# Generated by FakeRAM 2.0
VERSION 5.7 ;
BUSBITCHARS "[]" ;
PROPERTYDEFINITIONS
  MACRO width INTEGER ;
  MACRO depth INTEGER ;
  MACRO banks INTEGER ;
END PROPERTYDEFINITIONS
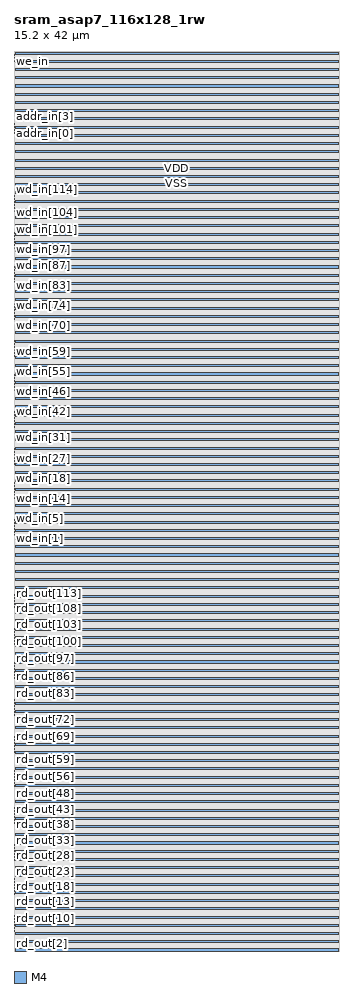
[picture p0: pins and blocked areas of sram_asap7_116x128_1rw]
MACRO sram_asap7_116x128_1rw
  PROPERTY width 116 ;
  PROPERTY depth 128 ;
  PROPERTY banks 1 ;
  FOREIGN sram_asap7_116x128_1rw 0 0 ;
  SYMMETRY X Y R90 ;
  SIZE 15.200 BY 42.000 ;
  CLASS BLOCK ;
  PIN rd_out[0]
    DIRECTION OUTPUT ;
    USE SIGNAL ;
    SHAPE ABUTMENT ;
    PORT
      LAYER M4 ;
      RECT 0.000 0.048 0.024 0.072 ;
    END
  END rd_out[0]
  PIN rd_out[1]
    DIRECTION OUTPUT ;
    USE SIGNAL ;
    SHAPE ABUTMENT ;
    PORT
      LAYER M4 ;
      RECT 0.000 0.192 0.024 0.216 ;
    END
  END rd_out[1]
  PIN rd_out[2]
    DIRECTION OUTPUT ;
    USE SIGNAL ;
    SHAPE ABUTMENT ;
    PORT
      LAYER M4 ;
      RECT 0.000 0.336 0.024 0.360 ;
    END
  END rd_out[2]
  PIN rd_out[3]
    DIRECTION OUTPUT ;
    USE SIGNAL ;
    SHAPE ABUTMENT ;
    PORT
      LAYER M4 ;
      RECT 0.000 0.480 0.024 0.504 ;
    END
  END rd_out[3]
  PIN rd_out[4]
    DIRECTION OUTPUT ;
    USE SIGNAL ;
    SHAPE ABUTMENT ;
    PORT
      LAYER M4 ;
      RECT 0.000 0.624 0.024 0.648 ;
    END
  END rd_out[4]
  PIN rd_out[5]
    DIRECTION OUTPUT ;
    USE SIGNAL ;
    SHAPE ABUTMENT ;
    PORT
      LAYER M4 ;
      RECT 0.000 0.768 0.024 0.792 ;
    END
  END rd_out[5]
  PIN rd_out[6]
    DIRECTION OUTPUT ;
    USE SIGNAL ;
    SHAPE ABUTMENT ;
    PORT
      LAYER M4 ;
      RECT 0.000 0.912 0.024 0.936 ;
    END
  END rd_out[6]
  PIN rd_out[7]
    DIRECTION OUTPUT ;
    USE SIGNAL ;
    SHAPE ABUTMENT ;
    PORT
      LAYER M4 ;
      RECT 0.000 1.056 0.024 1.080 ;
    END
  END rd_out[7]
  PIN rd_out[8]
    DIRECTION OUTPUT ;
    USE SIGNAL ;
    SHAPE ABUTMENT ;
    PORT
      LAYER M4 ;
      RECT 0.000 1.200 0.024 1.224 ;
    END
  END rd_out[8]
  PIN rd_out[9]
    DIRECTION OUTPUT ;
    USE SIGNAL ;
    SHAPE ABUTMENT ;
    PORT
      LAYER M4 ;
      RECT 0.000 1.344 0.024 1.368 ;
    END
  END rd_out[9]
  PIN rd_out[10]
    DIRECTION OUTPUT ;
    USE SIGNAL ;
    SHAPE ABUTMENT ;
    PORT
      LAYER M4 ;
      RECT 0.000 1.488 0.024 1.512 ;
    END
  END rd_out[10]
  PIN rd_out[11]
    DIRECTION OUTPUT ;
    USE SIGNAL ;
    SHAPE ABUTMENT ;
    PORT
      LAYER M4 ;
      RECT 0.000 1.632 0.024 1.656 ;
    END
  END rd_out[11]
  PIN rd_out[12]
    DIRECTION OUTPUT ;
    USE SIGNAL ;
    SHAPE ABUTMENT ;
    PORT
      LAYER M4 ;
      RECT 0.000 1.776 0.024 1.800 ;
    END
  END rd_out[12]
  PIN rd_out[13]
    DIRECTION OUTPUT ;
    USE SIGNAL ;
    SHAPE ABUTMENT ;
    PORT
      LAYER M4 ;
      RECT 0.000 1.920 0.024 1.944 ;
    END
  END rd_out[13]
  PIN rd_out[14]
    DIRECTION OUTPUT ;
    USE SIGNAL ;
    SHAPE ABUTMENT ;
    PORT
      LAYER M4 ;
      RECT 0.000 2.064 0.024 2.088 ;
    END
  END rd_out[14]
  PIN rd_out[15]
    DIRECTION OUTPUT ;
    USE SIGNAL ;
    SHAPE ABUTMENT ;
    PORT
      LAYER M4 ;
      RECT 0.000 2.208 0.024 2.232 ;
    END
  END rd_out[15]
  PIN rd_out[16]
    DIRECTION OUTPUT ;
    USE SIGNAL ;
    SHAPE ABUTMENT ;
    PORT
      LAYER M4 ;
      RECT 0.000 2.352 0.024 2.376 ;
    END
  END rd_out[16]
  PIN rd_out[17]
    DIRECTION OUTPUT ;
    USE SIGNAL ;
    SHAPE ABUTMENT ;
    PORT
      LAYER M4 ;
      RECT 0.000 2.496 0.024 2.520 ;
    END
  END rd_out[17]
  PIN rd_out[18]
    DIRECTION OUTPUT ;
    USE SIGNAL ;
    SHAPE ABUTMENT ;
    PORT
      LAYER M4 ;
      RECT 0.000 2.640 0.024 2.664 ;
    END
  END rd_out[18]
  PIN rd_out[19]
    DIRECTION OUTPUT ;
    USE SIGNAL ;
    SHAPE ABUTMENT ;
    PORT
      LAYER M4 ;
      RECT 0.000 2.784 0.024 2.808 ;
    END
  END rd_out[19]
  PIN rd_out[20]
    DIRECTION OUTPUT ;
    USE SIGNAL ;
    SHAPE ABUTMENT ;
    PORT
      LAYER M4 ;
      RECT 0.000 2.928 0.024 2.952 ;
    END
  END rd_out[20]
  PIN rd_out[21]
    DIRECTION OUTPUT ;
    USE SIGNAL ;
    SHAPE ABUTMENT ;
    PORT
      LAYER M4 ;
      RECT 0.000 3.072 0.024 3.096 ;
    END
  END rd_out[21]
  PIN rd_out[22]
    DIRECTION OUTPUT ;
    USE SIGNAL ;
    SHAPE ABUTMENT ;
    PORT
      LAYER M4 ;
      RECT 0.000 3.216 0.024 3.240 ;
    END
  END rd_out[22]
  PIN rd_out[23]
    DIRECTION OUTPUT ;
    USE SIGNAL ;
    SHAPE ABUTMENT ;
    PORT
      LAYER M4 ;
      RECT 0.000 3.360 0.024 3.384 ;
    END
  END rd_out[23]
  PIN rd_out[24]
    DIRECTION OUTPUT ;
    USE SIGNAL ;
    SHAPE ABUTMENT ;
    PORT
      LAYER M4 ;
      RECT 0.000 3.504 0.024 3.528 ;
    END
  END rd_out[24]
  PIN rd_out[25]
    DIRECTION OUTPUT ;
    USE SIGNAL ;
    SHAPE ABUTMENT ;
    PORT
      LAYER M4 ;
      RECT 0.000 3.648 0.024 3.672 ;
    END
  END rd_out[25]
  PIN rd_out[26]
    DIRECTION OUTPUT ;
    USE SIGNAL ;
    SHAPE ABUTMENT ;
    PORT
      LAYER M4 ;
      RECT 0.000 3.792 0.024 3.816 ;
    END
  END rd_out[26]
  PIN rd_out[27]
    DIRECTION OUTPUT ;
    USE SIGNAL ;
    SHAPE ABUTMENT ;
    PORT
      LAYER M4 ;
      RECT 0.000 3.936 0.024 3.960 ;
    END
  END rd_out[27]
  PIN rd_out[28]
    DIRECTION OUTPUT ;
    USE SIGNAL ;
    SHAPE ABUTMENT ;
    PORT
      LAYER M4 ;
      RECT 0.000 4.080 0.024 4.104 ;
    END
  END rd_out[28]
  PIN rd_out[29]
    DIRECTION OUTPUT ;
    USE SIGNAL ;
    SHAPE ABUTMENT ;
    PORT
      LAYER M4 ;
      RECT 0.000 4.224 0.024 4.248 ;
    END
  END rd_out[29]
  PIN rd_out[30]
    DIRECTION OUTPUT ;
    USE SIGNAL ;
    SHAPE ABUTMENT ;
    PORT
      LAYER M4 ;
      RECT 0.000 4.368 0.024 4.392 ;
    END
  END rd_out[30]
  PIN rd_out[31]
    DIRECTION OUTPUT ;
    USE SIGNAL ;
    SHAPE ABUTMENT ;
    PORT
      LAYER M4 ;
      RECT 0.000 4.512 0.024 4.536 ;
    END
  END rd_out[31]
  PIN rd_out[32]
    DIRECTION OUTPUT ;
    USE SIGNAL ;
    SHAPE ABUTMENT ;
    PORT
      LAYER M4 ;
      RECT 0.000 4.656 0.024 4.680 ;
    END
  END rd_out[32]
  PIN rd_out[33]
    DIRECTION OUTPUT ;
    USE SIGNAL ;
    SHAPE ABUTMENT ;
    PORT
      LAYER M4 ;
      RECT 0.000 4.800 0.024 4.824 ;
    END
  END rd_out[33]
  PIN rd_out[34]
    DIRECTION OUTPUT ;
    USE SIGNAL ;
    SHAPE ABUTMENT ;
    PORT
      LAYER M4 ;
      RECT 0.000 4.944 0.024 4.968 ;
    END
  END rd_out[34]
  PIN rd_out[35]
    DIRECTION OUTPUT ;
    USE SIGNAL ;
    SHAPE ABUTMENT ;
    PORT
      LAYER M4 ;
      RECT 0.000 5.088 0.024 5.112 ;
    END
  END rd_out[35]
  PIN rd_out[36]
    DIRECTION OUTPUT ;
    USE SIGNAL ;
    SHAPE ABUTMENT ;
    PORT
      LAYER M4 ;
      RECT 0.000 5.232 0.024 5.256 ;
    END
  END rd_out[36]
  PIN rd_out[37]
    DIRECTION OUTPUT ;
    USE SIGNAL ;
    SHAPE ABUTMENT ;
    PORT
      LAYER M4 ;
      RECT 0.000 5.376 0.024 5.400 ;
    END
  END rd_out[37]
  PIN rd_out[38]
    DIRECTION OUTPUT ;
    USE SIGNAL ;
    SHAPE ABUTMENT ;
    PORT
      LAYER M4 ;
      RECT 0.000 5.520 0.024 5.544 ;
    END
  END rd_out[38]
  PIN rd_out[39]
    DIRECTION OUTPUT ;
    USE SIGNAL ;
    SHAPE ABUTMENT ;
    PORT
      LAYER M4 ;
      RECT 0.000 5.664 0.024 5.688 ;
    END
  END rd_out[39]
  PIN rd_out[40]
    DIRECTION OUTPUT ;
    USE SIGNAL ;
    SHAPE ABUTMENT ;
    PORT
      LAYER M4 ;
      RECT 0.000 5.808 0.024 5.832 ;
    END
  END rd_out[40]
  PIN rd_out[41]
    DIRECTION OUTPUT ;
    USE SIGNAL ;
    SHAPE ABUTMENT ;
    PORT
      LAYER M4 ;
      RECT 0.000 5.952 0.024 5.976 ;
    END
  END rd_out[41]
  PIN rd_out[42]
    DIRECTION OUTPUT ;
    USE SIGNAL ;
    SHAPE ABUTMENT ;
    PORT
      LAYER M4 ;
      RECT 0.000 6.096 0.024 6.120 ;
    END
  END rd_out[42]
  PIN rd_out[43]
    DIRECTION OUTPUT ;
    USE SIGNAL ;
    SHAPE ABUTMENT ;
    PORT
      LAYER M4 ;
      RECT 0.000 6.240 0.024 6.264 ;
    END
  END rd_out[43]
  PIN rd_out[44]
    DIRECTION OUTPUT ;
    USE SIGNAL ;
    SHAPE ABUTMENT ;
    PORT
      LAYER M4 ;
      RECT 0.000 6.384 0.024 6.408 ;
    END
  END rd_out[44]
  PIN rd_out[45]
    DIRECTION OUTPUT ;
    USE SIGNAL ;
    SHAPE ABUTMENT ;
    PORT
      LAYER M4 ;
      RECT 0.000 6.528 0.024 6.552 ;
    END
  END rd_out[45]
  PIN rd_out[46]
    DIRECTION OUTPUT ;
    USE SIGNAL ;
    SHAPE ABUTMENT ;
    PORT
      LAYER M4 ;
      RECT 0.000 6.672 0.024 6.696 ;
    END
  END rd_out[46]
  PIN rd_out[47]
    DIRECTION OUTPUT ;
    USE SIGNAL ;
    SHAPE ABUTMENT ;
    PORT
      LAYER M4 ;
      RECT 0.000 6.816 0.024 6.840 ;
    END
  END rd_out[47]
  PIN rd_out[48]
    DIRECTION OUTPUT ;
    USE SIGNAL ;
    SHAPE ABUTMENT ;
    PORT
      LAYER M4 ;
      RECT 0.000 6.960 0.024 6.984 ;
    END
  END rd_out[48]
  PIN rd_out[49]
    DIRECTION OUTPUT ;
    USE SIGNAL ;
    SHAPE ABUTMENT ;
    PORT
      LAYER M4 ;
      RECT 0.000 7.104 0.024 7.128 ;
    END
  END rd_out[49]
  PIN rd_out[50]
    DIRECTION OUTPUT ;
    USE SIGNAL ;
    SHAPE ABUTMENT ;
    PORT
      LAYER M4 ;
      RECT 0.000 7.248 0.024 7.272 ;
    END
  END rd_out[50]
  PIN rd_out[51]
    DIRECTION OUTPUT ;
    USE SIGNAL ;
    SHAPE ABUTMENT ;
    PORT
      LAYER M4 ;
      RECT 0.000 7.392 0.024 7.416 ;
    END
  END rd_out[51]
  PIN rd_out[52]
    DIRECTION OUTPUT ;
    USE SIGNAL ;
    SHAPE ABUTMENT ;
    PORT
      LAYER M4 ;
      RECT 0.000 7.536 0.024 7.560 ;
    END
  END rd_out[52]
  PIN rd_out[53]
    DIRECTION OUTPUT ;
    USE SIGNAL ;
    SHAPE ABUTMENT ;
    PORT
      LAYER M4 ;
      RECT 0.000 7.680 0.024 7.704 ;
    END
  END rd_out[53]
  PIN rd_out[54]
    DIRECTION OUTPUT ;
    USE SIGNAL ;
    SHAPE ABUTMENT ;
    PORT
      LAYER M4 ;
      RECT 0.000 7.824 0.024 7.848 ;
    END
  END rd_out[54]
  PIN rd_out[55]
    DIRECTION OUTPUT ;
    USE SIGNAL ;
    SHAPE ABUTMENT ;
    PORT
      LAYER M4 ;
      RECT 0.000 7.968 0.024 7.992 ;
    END
  END rd_out[55]
  PIN rd_out[56]
    DIRECTION OUTPUT ;
    USE SIGNAL ;
    SHAPE ABUTMENT ;
    PORT
      LAYER M4 ;
      RECT 0.000 8.112 0.024 8.136 ;
    END
  END rd_out[56]
  PIN rd_out[57]
    DIRECTION OUTPUT ;
    USE SIGNAL ;
    SHAPE ABUTMENT ;
    PORT
      LAYER M4 ;
      RECT 0.000 8.256 0.024 8.280 ;
    END
  END rd_out[57]
  PIN rd_out[58]
    DIRECTION OUTPUT ;
    USE SIGNAL ;
    SHAPE ABUTMENT ;
    PORT
      LAYER M4 ;
      RECT 0.000 8.400 0.024 8.424 ;
    END
  END rd_out[58]
  PIN rd_out[59]
    DIRECTION OUTPUT ;
    USE SIGNAL ;
    SHAPE ABUTMENT ;
    PORT
      LAYER M4 ;
      RECT 0.000 8.544 0.024 8.568 ;
    END
  END rd_out[59]
  PIN rd_out[60]
    DIRECTION OUTPUT ;
    USE SIGNAL ;
    SHAPE ABUTMENT ;
    PORT
      LAYER M4 ;
      RECT 0.000 8.688 0.024 8.712 ;
    END
  END rd_out[60]
  PIN rd_out[61]
    DIRECTION OUTPUT ;
    USE SIGNAL ;
    SHAPE ABUTMENT ;
    PORT
      LAYER M4 ;
      RECT 0.000 8.832 0.024 8.856 ;
    END
  END rd_out[61]
  PIN rd_out[62]
    DIRECTION OUTPUT ;
    USE SIGNAL ;
    SHAPE ABUTMENT ;
    PORT
      LAYER M4 ;
      RECT 0.000 8.976 0.024 9.000 ;
    END
  END rd_out[62]
  PIN rd_out[63]
    DIRECTION OUTPUT ;
    USE SIGNAL ;
    SHAPE ABUTMENT ;
    PORT
      LAYER M4 ;
      RECT 0.000 9.120 0.024 9.144 ;
    END
  END rd_out[63]
  PIN rd_out[64]
    DIRECTION OUTPUT ;
    USE SIGNAL ;
    SHAPE ABUTMENT ;
    PORT
      LAYER M4 ;
      RECT 0.000 9.264 0.024 9.288 ;
    END
  END rd_out[64]
  PIN rd_out[65]
    DIRECTION OUTPUT ;
    USE SIGNAL ;
    SHAPE ABUTMENT ;
    PORT
      LAYER M4 ;
      RECT 0.000 9.408 0.024 9.432 ;
    END
  END rd_out[65]
  PIN rd_out[66]
    DIRECTION OUTPUT ;
    USE SIGNAL ;
    SHAPE ABUTMENT ;
    PORT
      LAYER M4 ;
      RECT 0.000 9.552 0.024 9.576 ;
    END
  END rd_out[66]
  PIN rd_out[67]
    DIRECTION OUTPUT ;
    USE SIGNAL ;
    SHAPE ABUTMENT ;
    PORT
      LAYER M4 ;
      RECT 0.000 9.696 0.024 9.720 ;
    END
  END rd_out[67]
  PIN rd_out[68]
    DIRECTION OUTPUT ;
    USE SIGNAL ;
    SHAPE ABUTMENT ;
    PORT
      LAYER M4 ;
      RECT 0.000 9.840 0.024 9.864 ;
    END
  END rd_out[68]
  PIN rd_out[69]
    DIRECTION OUTPUT ;
    USE SIGNAL ;
    SHAPE ABUTMENT ;
    PORT
      LAYER M4 ;
      RECT 0.000 9.984 0.024 10.008 ;
    END
  END rd_out[69]
  PIN rd_out[70]
    DIRECTION OUTPUT ;
    USE SIGNAL ;
    SHAPE ABUTMENT ;
    PORT
      LAYER M4 ;
      RECT 0.000 10.128 0.024 10.152 ;
    END
  END rd_out[70]
  PIN rd_out[71]
    DIRECTION OUTPUT ;
    USE SIGNAL ;
    SHAPE ABUTMENT ;
    PORT
      LAYER M4 ;
      RECT 0.000 10.272 0.024 10.296 ;
    END
  END rd_out[71]
  PIN rd_out[72]
    DIRECTION OUTPUT ;
    USE SIGNAL ;
    SHAPE ABUTMENT ;
    PORT
      LAYER M4 ;
      RECT 0.000 10.416 0.024 10.440 ;
    END
  END rd_out[72]
  PIN rd_out[73]
    DIRECTION OUTPUT ;
    USE SIGNAL ;
    SHAPE ABUTMENT ;
    PORT
      LAYER M4 ;
      RECT 0.000 10.560 0.024 10.584 ;
    END
  END rd_out[73]
  PIN rd_out[74]
    DIRECTION OUTPUT ;
    USE SIGNAL ;
    SHAPE ABUTMENT ;
    PORT
      LAYER M4 ;
      RECT 0.000 10.704 0.024 10.728 ;
    END
  END rd_out[74]
  PIN rd_out[75]
    DIRECTION OUTPUT ;
    USE SIGNAL ;
    SHAPE ABUTMENT ;
    PORT
      LAYER M4 ;
      RECT 0.000 10.848 0.024 10.872 ;
    END
  END rd_out[75]
  PIN rd_out[76]
    DIRECTION OUTPUT ;
    USE SIGNAL ;
    SHAPE ABUTMENT ;
    PORT
      LAYER M4 ;
      RECT 0.000 10.992 0.024 11.016 ;
    END
  END rd_out[76]
  PIN rd_out[77]
    DIRECTION OUTPUT ;
    USE SIGNAL ;
    SHAPE ABUTMENT ;
    PORT
      LAYER M4 ;
      RECT 0.000 11.136 0.024 11.160 ;
    END
  END rd_out[77]
  PIN rd_out[78]
    DIRECTION OUTPUT ;
    USE SIGNAL ;
    SHAPE ABUTMENT ;
    PORT
      LAYER M4 ;
      RECT 0.000 11.280 0.024 11.304 ;
    END
  END rd_out[78]
  PIN rd_out[79]
    DIRECTION OUTPUT ;
    USE SIGNAL ;
    SHAPE ABUTMENT ;
    PORT
      LAYER M4 ;
      RECT 0.000 11.424 0.024 11.448 ;
    END
  END rd_out[79]
  PIN rd_out[80]
    DIRECTION OUTPUT ;
    USE SIGNAL ;
    SHAPE ABUTMENT ;
    PORT
      LAYER M4 ;
      RECT 0.000 11.568 0.024 11.592 ;
    END
  END rd_out[80]
  PIN rd_out[81]
    DIRECTION OUTPUT ;
    USE SIGNAL ;
    SHAPE ABUTMENT ;
    PORT
      LAYER M4 ;
      RECT 0.000 11.712 0.024 11.736 ;
    END
  END rd_out[81]
  PIN rd_out[82]
    DIRECTION OUTPUT ;
    USE SIGNAL ;
    SHAPE ABUTMENT ;
    PORT
      LAYER M4 ;
      RECT 0.000 11.856 0.024 11.880 ;
    END
  END rd_out[82]
  PIN rd_out[83]
    DIRECTION OUTPUT ;
    USE SIGNAL ;
    SHAPE ABUTMENT ;
    PORT
      LAYER M4 ;
      RECT 0.000 12.000 0.024 12.024 ;
    END
  END rd_out[83]
  PIN rd_out[84]
    DIRECTION OUTPUT ;
    USE SIGNAL ;
    SHAPE ABUTMENT ;
    PORT
      LAYER M4 ;
      RECT 0.000 12.144 0.024 12.168 ;
    END
  END rd_out[84]
  PIN rd_out[85]
    DIRECTION OUTPUT ;
    USE SIGNAL ;
    SHAPE ABUTMENT ;
    PORT
      LAYER M4 ;
      RECT 0.000 12.288 0.024 12.312 ;
    END
  END rd_out[85]
  PIN rd_out[86]
    DIRECTION OUTPUT ;
    USE SIGNAL ;
    SHAPE ABUTMENT ;
    PORT
      LAYER M4 ;
      RECT 0.000 12.432 0.024 12.456 ;
    END
  END rd_out[86]
  PIN rd_out[87]
    DIRECTION OUTPUT ;
    USE SIGNAL ;
    SHAPE ABUTMENT ;
    PORT
      LAYER M4 ;
      RECT 0.000 12.576 0.024 12.600 ;
    END
  END rd_out[87]
  PIN rd_out[88]
    DIRECTION OUTPUT ;
    USE SIGNAL ;
    SHAPE ABUTMENT ;
    PORT
      LAYER M4 ;
      RECT 0.000 12.720 0.024 12.744 ;
    END
  END rd_out[88]
  PIN rd_out[89]
    DIRECTION OUTPUT ;
    USE SIGNAL ;
    SHAPE ABUTMENT ;
    PORT
      LAYER M4 ;
      RECT 0.000 12.864 0.024 12.888 ;
    END
  END rd_out[89]
  PIN rd_out[90]
    DIRECTION OUTPUT ;
    USE SIGNAL ;
    SHAPE ABUTMENT ;
    PORT
      LAYER M4 ;
      RECT 0.000 13.008 0.024 13.032 ;
    END
  END rd_out[90]
  PIN rd_out[91]
    DIRECTION OUTPUT ;
    USE SIGNAL ;
    SHAPE ABUTMENT ;
    PORT
      LAYER M4 ;
      RECT 0.000 13.152 0.024 13.176 ;
    END
  END rd_out[91]
  PIN rd_out[92]
    DIRECTION OUTPUT ;
    USE SIGNAL ;
    SHAPE ABUTMENT ;
    PORT
      LAYER M4 ;
      RECT 0.000 13.296 0.024 13.320 ;
    END
  END rd_out[92]
  PIN rd_out[93]
    DIRECTION OUTPUT ;
    USE SIGNAL ;
    SHAPE ABUTMENT ;
    PORT
      LAYER M4 ;
      RECT 0.000 13.440 0.024 13.464 ;
    END
  END rd_out[93]
  PIN rd_out[94]
    DIRECTION OUTPUT ;
    USE SIGNAL ;
    SHAPE ABUTMENT ;
    PORT
      LAYER M4 ;
      RECT 0.000 13.584 0.024 13.608 ;
    END
  END rd_out[94]
  PIN rd_out[95]
    DIRECTION OUTPUT ;
    USE SIGNAL ;
    SHAPE ABUTMENT ;
    PORT
      LAYER M4 ;
      RECT 0.000 13.728 0.024 13.752 ;
    END
  END rd_out[95]
  PIN rd_out[96]
    DIRECTION OUTPUT ;
    USE SIGNAL ;
    SHAPE ABUTMENT ;
    PORT
      LAYER M4 ;
      RECT 0.000 13.872 0.024 13.896 ;
    END
  END rd_out[96]
  PIN rd_out[97]
    DIRECTION OUTPUT ;
    USE SIGNAL ;
    SHAPE ABUTMENT ;
    PORT
      LAYER M4 ;
      RECT 0.000 14.016 0.024 14.040 ;
    END
  END rd_out[97]
  PIN rd_out[98]
    DIRECTION OUTPUT ;
    USE SIGNAL ;
    SHAPE ABUTMENT ;
    PORT
      LAYER M4 ;
      RECT 0.000 14.160 0.024 14.184 ;
    END
  END rd_out[98]
  PIN rd_out[99]
    DIRECTION OUTPUT ;
    USE SIGNAL ;
    SHAPE ABUTMENT ;
    PORT
      LAYER M4 ;
      RECT 0.000 14.304 0.024 14.328 ;
    END
  END rd_out[99]
  PIN rd_out[100]
    DIRECTION OUTPUT ;
    USE SIGNAL ;
    SHAPE ABUTMENT ;
    PORT
      LAYER M4 ;
      RECT 0.000 14.448 0.024 14.472 ;
    END
  END rd_out[100]
  PIN rd_out[101]
    DIRECTION OUTPUT ;
    USE SIGNAL ;
    SHAPE ABUTMENT ;
    PORT
      LAYER M4 ;
      RECT 0.000 14.592 0.024 14.616 ;
    END
  END rd_out[101]
  PIN rd_out[102]
    DIRECTION OUTPUT ;
    USE SIGNAL ;
    SHAPE ABUTMENT ;
    PORT
      LAYER M4 ;
      RECT 0.000 14.736 0.024 14.760 ;
    END
  END rd_out[102]
  PIN rd_out[103]
    DIRECTION OUTPUT ;
    USE SIGNAL ;
    SHAPE ABUTMENT ;
    PORT
      LAYER M4 ;
      RECT 0.000 14.880 0.024 14.904 ;
    END
  END rd_out[103]
  PIN rd_out[104]
    DIRECTION OUTPUT ;
    USE SIGNAL ;
    SHAPE ABUTMENT ;
    PORT
      LAYER M4 ;
      RECT 0.000 15.024 0.024 15.048 ;
    END
  END rd_out[104]
  PIN rd_out[105]
    DIRECTION OUTPUT ;
    USE SIGNAL ;
    SHAPE ABUTMENT ;
    PORT
      LAYER M4 ;
      RECT 0.000 15.168 0.024 15.192 ;
    END
  END rd_out[105]
  PIN rd_out[106]
    DIRECTION OUTPUT ;
    USE SIGNAL ;
    SHAPE ABUTMENT ;
    PORT
      LAYER M4 ;
      RECT 0.000 15.312 0.024 15.336 ;
    END
  END rd_out[106]
  PIN rd_out[107]
    DIRECTION OUTPUT ;
    USE SIGNAL ;
    SHAPE ABUTMENT ;
    PORT
      LAYER M4 ;
      RECT 0.000 15.456 0.024 15.480 ;
    END
  END rd_out[107]
  PIN rd_out[108]
    DIRECTION OUTPUT ;
    USE SIGNAL ;
    SHAPE ABUTMENT ;
    PORT
      LAYER M4 ;
      RECT 0.000 15.600 0.024 15.624 ;
    END
  END rd_out[108]
  PIN rd_out[109]
    DIRECTION OUTPUT ;
    USE SIGNAL ;
    SHAPE ABUTMENT ;
    PORT
      LAYER M4 ;
      RECT 0.000 15.744 0.024 15.768 ;
    END
  END rd_out[109]
  PIN rd_out[110]
    DIRECTION OUTPUT ;
    USE SIGNAL ;
    SHAPE ABUTMENT ;
    PORT
      LAYER M4 ;
      RECT 0.000 15.888 0.024 15.912 ;
    END
  END rd_out[110]
  PIN rd_out[111]
    DIRECTION OUTPUT ;
    USE SIGNAL ;
    SHAPE ABUTMENT ;
    PORT
      LAYER M4 ;
      RECT 0.000 16.032 0.024 16.056 ;
    END
  END rd_out[111]
  PIN rd_out[112]
    DIRECTION OUTPUT ;
    USE SIGNAL ;
    SHAPE ABUTMENT ;
    PORT
      LAYER M4 ;
      RECT 0.000 16.176 0.024 16.200 ;
    END
  END rd_out[112]
  PIN rd_out[113]
    DIRECTION OUTPUT ;
    USE SIGNAL ;
    SHAPE ABUTMENT ;
    PORT
      LAYER M4 ;
      RECT 0.000 16.320 0.024 16.344 ;
    END
  END rd_out[113]
  PIN rd_out[114]
    DIRECTION OUTPUT ;
    USE SIGNAL ;
    SHAPE ABUTMENT ;
    PORT
      LAYER M4 ;
      RECT 0.000 16.464 0.024 16.488 ;
    END
  END rd_out[114]
  PIN rd_out[115]
    DIRECTION OUTPUT ;
    USE SIGNAL ;
    SHAPE ABUTMENT ;
    PORT
      LAYER M4 ;
      RECT 0.000 16.608 0.024 16.632 ;
    END
  END rd_out[115]
  PIN wd_in[0]
    DIRECTION INPUT ;
    USE SIGNAL ;
    SHAPE ABUTMENT ;
    PORT
      LAYER M4 ;
      RECT 0.000 19.104 0.024 19.128 ;
    END
  END wd_in[0]
  PIN wd_in[1]
    DIRECTION INPUT ;
    USE SIGNAL ;
    SHAPE ABUTMENT ;
    PORT
      LAYER M4 ;
      RECT 0.000 19.248 0.024 19.272 ;
    END
  END wd_in[1]
  PIN wd_in[2]
    DIRECTION INPUT ;
    USE SIGNAL ;
    SHAPE ABUTMENT ;
    PORT
      LAYER M4 ;
      RECT 0.000 19.392 0.024 19.416 ;
    END
  END wd_in[2]
  PIN wd_in[3]
    DIRECTION INPUT ;
    USE SIGNAL ;
    SHAPE ABUTMENT ;
    PORT
      LAYER M4 ;
      RECT 0.000 19.536 0.024 19.560 ;
    END
  END wd_in[3]
  PIN wd_in[4]
    DIRECTION INPUT ;
    USE SIGNAL ;
    SHAPE ABUTMENT ;
    PORT
      LAYER M4 ;
      RECT 0.000 19.680 0.024 19.704 ;
    END
  END wd_in[4]
  PIN wd_in[5]
    DIRECTION INPUT ;
    USE SIGNAL ;
    SHAPE ABUTMENT ;
    PORT
      LAYER M4 ;
      RECT 0.000 19.824 0.024 19.848 ;
    END
  END wd_in[5]
  PIN wd_in[6]
    DIRECTION INPUT ;
    USE SIGNAL ;
    SHAPE ABUTMENT ;
    PORT
      LAYER M4 ;
      RECT 0.000 19.968 0.024 19.992 ;
    END
  END wd_in[6]
  PIN wd_in[7]
    DIRECTION INPUT ;
    USE SIGNAL ;
    SHAPE ABUTMENT ;
    PORT
      LAYER M4 ;
      RECT 0.000 20.112 0.024 20.136 ;
    END
  END wd_in[7]
  PIN wd_in[8]
    DIRECTION INPUT ;
    USE SIGNAL ;
    SHAPE ABUTMENT ;
    PORT
      LAYER M4 ;
      RECT 0.000 20.256 0.024 20.280 ;
    END
  END wd_in[8]
  PIN wd_in[9]
    DIRECTION INPUT ;
    USE SIGNAL ;
    SHAPE ABUTMENT ;
    PORT
      LAYER M4 ;
      RECT 0.000 20.400 0.024 20.424 ;
    END
  END wd_in[9]
  PIN wd_in[10]
    DIRECTION INPUT ;
    USE SIGNAL ;
    SHAPE ABUTMENT ;
    PORT
      LAYER M4 ;
      RECT 0.000 20.544 0.024 20.568 ;
    END
  END wd_in[10]
  PIN wd_in[11]
    DIRECTION INPUT ;
    USE SIGNAL ;
    SHAPE ABUTMENT ;
    PORT
      LAYER M4 ;
      RECT 0.000 20.688 0.024 20.712 ;
    END
  END wd_in[11]
  PIN wd_in[12]
    DIRECTION INPUT ;
    USE SIGNAL ;
    SHAPE ABUTMENT ;
    PORT
      LAYER M4 ;
      RECT 0.000 20.832 0.024 20.856 ;
    END
  END wd_in[12]
  PIN wd_in[13]
    DIRECTION INPUT ;
    USE SIGNAL ;
    SHAPE ABUTMENT ;
    PORT
      LAYER M4 ;
      RECT 0.000 20.976 0.024 21.000 ;
    END
  END wd_in[13]
  PIN wd_in[14]
    DIRECTION INPUT ;
    USE SIGNAL ;
    SHAPE ABUTMENT ;
    PORT
      LAYER M4 ;
      RECT 0.000 21.120 0.024 21.144 ;
    END
  END wd_in[14]
  PIN wd_in[15]
    DIRECTION INPUT ;
    USE SIGNAL ;
    SHAPE ABUTMENT ;
    PORT
      LAYER M4 ;
      RECT 0.000 21.264 0.024 21.288 ;
    END
  END wd_in[15]
  PIN wd_in[16]
    DIRECTION INPUT ;
    USE SIGNAL ;
    SHAPE ABUTMENT ;
    PORT
      LAYER M4 ;
      RECT 0.000 21.408 0.024 21.432 ;
    END
  END wd_in[16]
  PIN wd_in[17]
    DIRECTION INPUT ;
    USE SIGNAL ;
    SHAPE ABUTMENT ;
    PORT
      LAYER M4 ;
      RECT 0.000 21.552 0.024 21.576 ;
    END
  END wd_in[17]
  PIN wd_in[18]
    DIRECTION INPUT ;
    USE SIGNAL ;
    SHAPE ABUTMENT ;
    PORT
      LAYER M4 ;
      RECT 0.000 21.696 0.024 21.720 ;
    END
  END wd_in[18]
  PIN wd_in[19]
    DIRECTION INPUT ;
    USE SIGNAL ;
    SHAPE ABUTMENT ;
    PORT
      LAYER M4 ;
      RECT 0.000 21.840 0.024 21.864 ;
    END
  END wd_in[19]
  PIN wd_in[20]
    DIRECTION INPUT ;
    USE SIGNAL ;
    SHAPE ABUTMENT ;
    PORT
      LAYER M4 ;
      RECT 0.000 21.984 0.024 22.008 ;
    END
  END wd_in[20]
  PIN wd_in[21]
    DIRECTION INPUT ;
    USE SIGNAL ;
    SHAPE ABUTMENT ;
    PORT
      LAYER M4 ;
      RECT 0.000 22.128 0.024 22.152 ;
    END
  END wd_in[21]
  PIN wd_in[22]
    DIRECTION INPUT ;
    USE SIGNAL ;
    SHAPE ABUTMENT ;
    PORT
      LAYER M4 ;
      RECT 0.000 22.272 0.024 22.296 ;
    END
  END wd_in[22]
  PIN wd_in[23]
    DIRECTION INPUT ;
    USE SIGNAL ;
    SHAPE ABUTMENT ;
    PORT
      LAYER M4 ;
      RECT 0.000 22.416 0.024 22.440 ;
    END
  END wd_in[23]
  PIN wd_in[24]
    DIRECTION INPUT ;
    USE SIGNAL ;
    SHAPE ABUTMENT ;
    PORT
      LAYER M4 ;
      RECT 0.000 22.560 0.024 22.584 ;
    END
  END wd_in[24]
  PIN wd_in[25]
    DIRECTION INPUT ;
    USE SIGNAL ;
    SHAPE ABUTMENT ;
    PORT
      LAYER M4 ;
      RECT 0.000 22.704 0.024 22.728 ;
    END
  END wd_in[25]
  PIN wd_in[26]
    DIRECTION INPUT ;
    USE SIGNAL ;
    SHAPE ABUTMENT ;
    PORT
      LAYER M4 ;
      RECT 0.000 22.848 0.024 22.872 ;
    END
  END wd_in[26]
  PIN wd_in[27]
    DIRECTION INPUT ;
    USE SIGNAL ;
    SHAPE ABUTMENT ;
    PORT
      LAYER M4 ;
      RECT 0.000 22.992 0.024 23.016 ;
    END
  END wd_in[27]
  PIN wd_in[28]
    DIRECTION INPUT ;
    USE SIGNAL ;
    SHAPE ABUTMENT ;
    PORT
      LAYER M4 ;
      RECT 0.000 23.136 0.024 23.160 ;
    END
  END wd_in[28]
  PIN wd_in[29]
    DIRECTION INPUT ;
    USE SIGNAL ;
    SHAPE ABUTMENT ;
    PORT
      LAYER M4 ;
      RECT 0.000 23.280 0.024 23.304 ;
    END
  END wd_in[29]
  PIN wd_in[30]
    DIRECTION INPUT ;
    USE SIGNAL ;
    SHAPE ABUTMENT ;
    PORT
      LAYER M4 ;
      RECT 0.000 23.424 0.024 23.448 ;
    END
  END wd_in[30]
  PIN wd_in[31]
    DIRECTION INPUT ;
    USE SIGNAL ;
    SHAPE ABUTMENT ;
    PORT
      LAYER M4 ;
      RECT 0.000 23.568 0.024 23.592 ;
    END
  END wd_in[31]
  PIN wd_in[32]
    DIRECTION INPUT ;
    USE SIGNAL ;
    SHAPE ABUTMENT ;
    PORT
      LAYER M4 ;
      RECT 0.000 23.712 0.024 23.736 ;
    END
  END wd_in[32]
  PIN wd_in[33]
    DIRECTION INPUT ;
    USE SIGNAL ;
    SHAPE ABUTMENT ;
    PORT
      LAYER M4 ;
      RECT 0.000 23.856 0.024 23.880 ;
    END
  END wd_in[33]
  PIN wd_in[34]
    DIRECTION INPUT ;
    USE SIGNAL ;
    SHAPE ABUTMENT ;
    PORT
      LAYER M4 ;
      RECT 0.000 24.000 0.024 24.024 ;
    END
  END wd_in[34]
  PIN wd_in[35]
    DIRECTION INPUT ;
    USE SIGNAL ;
    SHAPE ABUTMENT ;
    PORT
      LAYER M4 ;
      RECT 0.000 24.144 0.024 24.168 ;
    END
  END wd_in[35]
  PIN wd_in[36]
    DIRECTION INPUT ;
    USE SIGNAL ;
    SHAPE ABUTMENT ;
    PORT
      LAYER M4 ;
      RECT 0.000 24.288 0.024 24.312 ;
    END
  END wd_in[36]
  PIN wd_in[37]
    DIRECTION INPUT ;
    USE SIGNAL ;
    SHAPE ABUTMENT ;
    PORT
      LAYER M4 ;
      RECT 0.000 24.432 0.024 24.456 ;
    END
  END wd_in[37]
  PIN wd_in[38]
    DIRECTION INPUT ;
    USE SIGNAL ;
    SHAPE ABUTMENT ;
    PORT
      LAYER M4 ;
      RECT 0.000 24.576 0.024 24.600 ;
    END
  END wd_in[38]
  PIN wd_in[39]
    DIRECTION INPUT ;
    USE SIGNAL ;
    SHAPE ABUTMENT ;
    PORT
      LAYER M4 ;
      RECT 0.000 24.720 0.024 24.744 ;
    END
  END wd_in[39]
  PIN wd_in[40]
    DIRECTION INPUT ;
    USE SIGNAL ;
    SHAPE ABUTMENT ;
    PORT
      LAYER M4 ;
      RECT 0.000 24.864 0.024 24.888 ;
    END
  END wd_in[40]
  PIN wd_in[41]
    DIRECTION INPUT ;
    USE SIGNAL ;
    SHAPE ABUTMENT ;
    PORT
      LAYER M4 ;
      RECT 0.000 25.008 0.024 25.032 ;
    END
  END wd_in[41]
  PIN wd_in[42]
    DIRECTION INPUT ;
    USE SIGNAL ;
    SHAPE ABUTMENT ;
    PORT
      LAYER M4 ;
      RECT 0.000 25.152 0.024 25.176 ;
    END
  END wd_in[42]
  PIN wd_in[43]
    DIRECTION INPUT ;
    USE SIGNAL ;
    SHAPE ABUTMENT ;
    PORT
      LAYER M4 ;
      RECT 0.000 25.296 0.024 25.320 ;
    END
  END wd_in[43]
  PIN wd_in[44]
    DIRECTION INPUT ;
    USE SIGNAL ;
    SHAPE ABUTMENT ;
    PORT
      LAYER M4 ;
      RECT 0.000 25.440 0.024 25.464 ;
    END
  END wd_in[44]
  PIN wd_in[45]
    DIRECTION INPUT ;
    USE SIGNAL ;
    SHAPE ABUTMENT ;
    PORT
      LAYER M4 ;
      RECT 0.000 25.584 0.024 25.608 ;
    END
  END wd_in[45]
  PIN wd_in[46]
    DIRECTION INPUT ;
    USE SIGNAL ;
    SHAPE ABUTMENT ;
    PORT
      LAYER M4 ;
      RECT 0.000 25.728 0.024 25.752 ;
    END
  END wd_in[46]
  PIN wd_in[47]
    DIRECTION INPUT ;
    USE SIGNAL ;
    SHAPE ABUTMENT ;
    PORT
      LAYER M4 ;
      RECT 0.000 25.872 0.024 25.896 ;
    END
  END wd_in[47]
  PIN wd_in[48]
    DIRECTION INPUT ;
    USE SIGNAL ;
    SHAPE ABUTMENT ;
    PORT
      LAYER M4 ;
      RECT 0.000 26.016 0.024 26.040 ;
    END
  END wd_in[48]
  PIN wd_in[49]
    DIRECTION INPUT ;
    USE SIGNAL ;
    SHAPE ABUTMENT ;
    PORT
      LAYER M4 ;
      RECT 0.000 26.160 0.024 26.184 ;
    END
  END wd_in[49]
  PIN wd_in[50]
    DIRECTION INPUT ;
    USE SIGNAL ;
    SHAPE ABUTMENT ;
    PORT
      LAYER M4 ;
      RECT 0.000 26.304 0.024 26.328 ;
    END
  END wd_in[50]
  PIN wd_in[51]
    DIRECTION INPUT ;
    USE SIGNAL ;
    SHAPE ABUTMENT ;
    PORT
      LAYER M4 ;
      RECT 0.000 26.448 0.024 26.472 ;
    END
  END wd_in[51]
  PIN wd_in[52]
    DIRECTION INPUT ;
    USE SIGNAL ;
    SHAPE ABUTMENT ;
    PORT
      LAYER M4 ;
      RECT 0.000 26.592 0.024 26.616 ;
    END
  END wd_in[52]
  PIN wd_in[53]
    DIRECTION INPUT ;
    USE SIGNAL ;
    SHAPE ABUTMENT ;
    PORT
      LAYER M4 ;
      RECT 0.000 26.736 0.024 26.760 ;
    END
  END wd_in[53]
  PIN wd_in[54]
    DIRECTION INPUT ;
    USE SIGNAL ;
    SHAPE ABUTMENT ;
    PORT
      LAYER M4 ;
      RECT 0.000 26.880 0.024 26.904 ;
    END
  END wd_in[54]
  PIN wd_in[55]
    DIRECTION INPUT ;
    USE SIGNAL ;
    SHAPE ABUTMENT ;
    PORT
      LAYER M4 ;
      RECT 0.000 27.024 0.024 27.048 ;
    END
  END wd_in[55]
  PIN wd_in[56]
    DIRECTION INPUT ;
    USE SIGNAL ;
    SHAPE ABUTMENT ;
    PORT
      LAYER M4 ;
      RECT 0.000 27.168 0.024 27.192 ;
    END
  END wd_in[56]
  PIN wd_in[57]
    DIRECTION INPUT ;
    USE SIGNAL ;
    SHAPE ABUTMENT ;
    PORT
      LAYER M4 ;
      RECT 0.000 27.312 0.024 27.336 ;
    END
  END wd_in[57]
  PIN wd_in[58]
    DIRECTION INPUT ;
    USE SIGNAL ;
    SHAPE ABUTMENT ;
    PORT
      LAYER M4 ;
      RECT 0.000 27.456 0.024 27.480 ;
    END
  END wd_in[58]
  PIN wd_in[59]
    DIRECTION INPUT ;
    USE SIGNAL ;
    SHAPE ABUTMENT ;
    PORT
      LAYER M4 ;
      RECT 0.000 27.600 0.024 27.624 ;
    END
  END wd_in[59]
  PIN wd_in[60]
    DIRECTION INPUT ;
    USE SIGNAL ;
    SHAPE ABUTMENT ;
    PORT
      LAYER M4 ;
      RECT 0.000 27.744 0.024 27.768 ;
    END
  END wd_in[60]
  PIN wd_in[61]
    DIRECTION INPUT ;
    USE SIGNAL ;
    SHAPE ABUTMENT ;
    PORT
      LAYER M4 ;
      RECT 0.000 27.888 0.024 27.912 ;
    END
  END wd_in[61]
  PIN wd_in[62]
    DIRECTION INPUT ;
    USE SIGNAL ;
    SHAPE ABUTMENT ;
    PORT
      LAYER M4 ;
      RECT 0.000 28.032 0.024 28.056 ;
    END
  END wd_in[62]
  PIN wd_in[63]
    DIRECTION INPUT ;
    USE SIGNAL ;
    SHAPE ABUTMENT ;
    PORT
      LAYER M4 ;
      RECT 0.000 28.176 0.024 28.200 ;
    END
  END wd_in[63]
  PIN wd_in[64]
    DIRECTION INPUT ;
    USE SIGNAL ;
    SHAPE ABUTMENT ;
    PORT
      LAYER M4 ;
      RECT 0.000 28.320 0.024 28.344 ;
    END
  END wd_in[64]
  PIN wd_in[65]
    DIRECTION INPUT ;
    USE SIGNAL ;
    SHAPE ABUTMENT ;
    PORT
      LAYER M4 ;
      RECT 0.000 28.464 0.024 28.488 ;
    END
  END wd_in[65]
  PIN wd_in[66]
    DIRECTION INPUT ;
    USE SIGNAL ;
    SHAPE ABUTMENT ;
    PORT
      LAYER M4 ;
      RECT 0.000 28.608 0.024 28.632 ;
    END
  END wd_in[66]
  PIN wd_in[67]
    DIRECTION INPUT ;
    USE SIGNAL ;
    SHAPE ABUTMENT ;
    PORT
      LAYER M4 ;
      RECT 0.000 28.752 0.024 28.776 ;
    END
  END wd_in[67]
  PIN wd_in[68]
    DIRECTION INPUT ;
    USE SIGNAL ;
    SHAPE ABUTMENT ;
    PORT
      LAYER M4 ;
      RECT 0.000 28.896 0.024 28.920 ;
    END
  END wd_in[68]
  PIN wd_in[69]
    DIRECTION INPUT ;
    USE SIGNAL ;
    SHAPE ABUTMENT ;
    PORT
      LAYER M4 ;
      RECT 0.000 29.040 0.024 29.064 ;
    END
  END wd_in[69]
  PIN wd_in[70]
    DIRECTION INPUT ;
    USE SIGNAL ;
    SHAPE ABUTMENT ;
    PORT
      LAYER M4 ;
      RECT 0.000 29.184 0.024 29.208 ;
    END
  END wd_in[70]
  PIN wd_in[71]
    DIRECTION INPUT ;
    USE SIGNAL ;
    SHAPE ABUTMENT ;
    PORT
      LAYER M4 ;
      RECT 0.000 29.328 0.024 29.352 ;
    END
  END wd_in[71]
  PIN wd_in[72]
    DIRECTION INPUT ;
    USE SIGNAL ;
    SHAPE ABUTMENT ;
    PORT
      LAYER M4 ;
      RECT 0.000 29.472 0.024 29.496 ;
    END
  END wd_in[72]
  PIN wd_in[73]
    DIRECTION INPUT ;
    USE SIGNAL ;
    SHAPE ABUTMENT ;
    PORT
      LAYER M4 ;
      RECT 0.000 29.616 0.024 29.640 ;
    END
  END wd_in[73]
  PIN wd_in[74]
    DIRECTION INPUT ;
    USE SIGNAL ;
    SHAPE ABUTMENT ;
    PORT
      LAYER M4 ;
      RECT 0.000 29.760 0.024 29.784 ;
    END
  END wd_in[74]
  PIN wd_in[75]
    DIRECTION INPUT ;
    USE SIGNAL ;
    SHAPE ABUTMENT ;
    PORT
      LAYER M4 ;
      RECT 0.000 29.904 0.024 29.928 ;
    END
  END wd_in[75]
  PIN wd_in[76]
    DIRECTION INPUT ;
    USE SIGNAL ;
    SHAPE ABUTMENT ;
    PORT
      LAYER M4 ;
      RECT 0.000 30.048 0.024 30.072 ;
    END
  END wd_in[76]
  PIN wd_in[77]
    DIRECTION INPUT ;
    USE SIGNAL ;
    SHAPE ABUTMENT ;
    PORT
      LAYER M4 ;
      RECT 0.000 30.192 0.024 30.216 ;
    END
  END wd_in[77]
  PIN wd_in[78]
    DIRECTION INPUT ;
    USE SIGNAL ;
    SHAPE ABUTMENT ;
    PORT
      LAYER M4 ;
      RECT 0.000 30.336 0.024 30.360 ;
    END
  END wd_in[78]
  PIN wd_in[79]
    DIRECTION INPUT ;
    USE SIGNAL ;
    SHAPE ABUTMENT ;
    PORT
      LAYER M4 ;
      RECT 0.000 30.480 0.024 30.504 ;
    END
  END wd_in[79]
  PIN wd_in[80]
    DIRECTION INPUT ;
    USE SIGNAL ;
    SHAPE ABUTMENT ;
    PORT
      LAYER M4 ;
      RECT 0.000 30.624 0.024 30.648 ;
    END
  END wd_in[80]
  PIN wd_in[81]
    DIRECTION INPUT ;
    USE SIGNAL ;
    SHAPE ABUTMENT ;
    PORT
      LAYER M4 ;
      RECT 0.000 30.768 0.024 30.792 ;
    END
  END wd_in[81]
  PIN wd_in[82]
    DIRECTION INPUT ;
    USE SIGNAL ;
    SHAPE ABUTMENT ;
    PORT
      LAYER M4 ;
      RECT 0.000 30.912 0.024 30.936 ;
    END
  END wd_in[82]
  PIN wd_in[83]
    DIRECTION INPUT ;
    USE SIGNAL ;
    SHAPE ABUTMENT ;
    PORT
      LAYER M4 ;
      RECT 0.000 31.056 0.024 31.080 ;
    END
  END wd_in[83]
  PIN wd_in[84]
    DIRECTION INPUT ;
    USE SIGNAL ;
    SHAPE ABUTMENT ;
    PORT
      LAYER M4 ;
      RECT 0.000 31.200 0.024 31.224 ;
    END
  END wd_in[84]
  PIN wd_in[85]
    DIRECTION INPUT ;
    USE SIGNAL ;
    SHAPE ABUTMENT ;
    PORT
      LAYER M4 ;
      RECT 0.000 31.344 0.024 31.368 ;
    END
  END wd_in[85]
  PIN wd_in[86]
    DIRECTION INPUT ;
    USE SIGNAL ;
    SHAPE ABUTMENT ;
    PORT
      LAYER M4 ;
      RECT 0.000 31.488 0.024 31.512 ;
    END
  END wd_in[86]
  PIN wd_in[87]
    DIRECTION INPUT ;
    USE SIGNAL ;
    SHAPE ABUTMENT ;
    PORT
      LAYER M4 ;
      RECT 0.000 31.632 0.024 31.656 ;
    END
  END wd_in[87]
  PIN wd_in[88]
    DIRECTION INPUT ;
    USE SIGNAL ;
    SHAPE ABUTMENT ;
    PORT
      LAYER M4 ;
      RECT 0.000 31.776 0.024 31.800 ;
    END
  END wd_in[88]
  PIN wd_in[89]
    DIRECTION INPUT ;
    USE SIGNAL ;
    SHAPE ABUTMENT ;
    PORT
      LAYER M4 ;
      RECT 0.000 31.920 0.024 31.944 ;
    END
  END wd_in[89]
  PIN wd_in[90]
    DIRECTION INPUT ;
    USE SIGNAL ;
    SHAPE ABUTMENT ;
    PORT
      LAYER M4 ;
      RECT 0.000 32.064 0.024 32.088 ;
    END
  END wd_in[90]
  PIN wd_in[91]
    DIRECTION INPUT ;
    USE SIGNAL ;
    SHAPE ABUTMENT ;
    PORT
      LAYER M4 ;
      RECT 0.000 32.208 0.024 32.232 ;
    END
  END wd_in[91]
  PIN wd_in[92]
    DIRECTION INPUT ;
    USE SIGNAL ;
    SHAPE ABUTMENT ;
    PORT
      LAYER M4 ;
      RECT 0.000 32.352 0.024 32.376 ;
    END
  END wd_in[92]
  PIN wd_in[93]
    DIRECTION INPUT ;
    USE SIGNAL ;
    SHAPE ABUTMENT ;
    PORT
      LAYER M4 ;
      RECT 0.000 32.496 0.024 32.520 ;
    END
  END wd_in[93]
  PIN wd_in[94]
    DIRECTION INPUT ;
    USE SIGNAL ;
    SHAPE ABUTMENT ;
    PORT
      LAYER M4 ;
      RECT 0.000 32.640 0.024 32.664 ;
    END
  END wd_in[94]
  PIN wd_in[95]
    DIRECTION INPUT ;
    USE SIGNAL ;
    SHAPE ABUTMENT ;
    PORT
      LAYER M4 ;
      RECT 0.000 32.784 0.024 32.808 ;
    END
  END wd_in[95]
  PIN wd_in[96]
    DIRECTION INPUT ;
    USE SIGNAL ;
    SHAPE ABUTMENT ;
    PORT
      LAYER M4 ;
      RECT 0.000 32.928 0.024 32.952 ;
    END
  END wd_in[96]
  PIN wd_in[97]
    DIRECTION INPUT ;
    USE SIGNAL ;
    SHAPE ABUTMENT ;
    PORT
      LAYER M4 ;
      RECT 0.000 33.072 0.024 33.096 ;
    END
  END wd_in[97]
  PIN wd_in[98]
    DIRECTION INPUT ;
    USE SIGNAL ;
    SHAPE ABUTMENT ;
    PORT
      LAYER M4 ;
      RECT 0.000 33.216 0.024 33.240 ;
    END
  END wd_in[98]
  PIN wd_in[99]
    DIRECTION INPUT ;
    USE SIGNAL ;
    SHAPE ABUTMENT ;
    PORT
      LAYER M4 ;
      RECT 0.000 33.360 0.024 33.384 ;
    END
  END wd_in[99]
  PIN wd_in[100]
    DIRECTION INPUT ;
    USE SIGNAL ;
    SHAPE ABUTMENT ;
    PORT
      LAYER M4 ;
      RECT 0.000 33.504 0.024 33.528 ;
    END
  END wd_in[100]
  PIN wd_in[101]
    DIRECTION INPUT ;
    USE SIGNAL ;
    SHAPE ABUTMENT ;
    PORT
      LAYER M4 ;
      RECT 0.000 33.648 0.024 33.672 ;
    END
  END wd_in[101]
  PIN wd_in[102]
    DIRECTION INPUT ;
    USE SIGNAL ;
    SHAPE ABUTMENT ;
    PORT
      LAYER M4 ;
      RECT 0.000 33.792 0.024 33.816 ;
    END
  END wd_in[102]
  PIN wd_in[103]
    DIRECTION INPUT ;
    USE SIGNAL ;
    SHAPE ABUTMENT ;
    PORT
      LAYER M4 ;
      RECT 0.000 33.936 0.024 33.960 ;
    END
  END wd_in[103]
  PIN wd_in[104]
    DIRECTION INPUT ;
    USE SIGNAL ;
    SHAPE ABUTMENT ;
    PORT
      LAYER M4 ;
      RECT 0.000 34.080 0.024 34.104 ;
    END
  END wd_in[104]
  PIN wd_in[105]
    DIRECTION INPUT ;
    USE SIGNAL ;
    SHAPE ABUTMENT ;
    PORT
      LAYER M4 ;
      RECT 0.000 34.224 0.024 34.248 ;
    END
  END wd_in[105]
  PIN wd_in[106]
    DIRECTION INPUT ;
    USE SIGNAL ;
    SHAPE ABUTMENT ;
    PORT
      LAYER M4 ;
      RECT 0.000 34.368 0.024 34.392 ;
    END
  END wd_in[106]
  PIN wd_in[107]
    DIRECTION INPUT ;
    USE SIGNAL ;
    SHAPE ABUTMENT ;
    PORT
      LAYER M4 ;
      RECT 0.000 34.512 0.024 34.536 ;
    END
  END wd_in[107]
  PIN wd_in[108]
    DIRECTION INPUT ;
    USE SIGNAL ;
    SHAPE ABUTMENT ;
    PORT
      LAYER M4 ;
      RECT 0.000 34.656 0.024 34.680 ;
    END
  END wd_in[108]
  PIN wd_in[109]
    DIRECTION INPUT ;
    USE SIGNAL ;
    SHAPE ABUTMENT ;
    PORT
      LAYER M4 ;
      RECT 0.000 34.800 0.024 34.824 ;
    END
  END wd_in[109]
  PIN wd_in[110]
    DIRECTION INPUT ;
    USE SIGNAL ;
    SHAPE ABUTMENT ;
    PORT
      LAYER M4 ;
      RECT 0.000 34.944 0.024 34.968 ;
    END
  END wd_in[110]
  PIN wd_in[111]
    DIRECTION INPUT ;
    USE SIGNAL ;
    SHAPE ABUTMENT ;
    PORT
      LAYER M4 ;
      RECT 0.000 35.088 0.024 35.112 ;
    END
  END wd_in[111]
  PIN wd_in[112]
    DIRECTION INPUT ;
    USE SIGNAL ;
    SHAPE ABUTMENT ;
    PORT
      LAYER M4 ;
      RECT 0.000 35.232 0.024 35.256 ;
    END
  END wd_in[112]
  PIN wd_in[113]
    DIRECTION INPUT ;
    USE SIGNAL ;
    SHAPE ABUTMENT ;
    PORT
      LAYER M4 ;
      RECT 0.000 35.376 0.024 35.400 ;
    END
  END wd_in[113]
  PIN wd_in[114]
    DIRECTION INPUT ;
    USE SIGNAL ;
    SHAPE ABUTMENT ;
    PORT
      LAYER M4 ;
      RECT 0.000 35.520 0.024 35.544 ;
    END
  END wd_in[114]
  PIN wd_in[115]
    DIRECTION INPUT ;
    USE SIGNAL ;
    SHAPE ABUTMENT ;
    PORT
      LAYER M4 ;
      RECT 0.000 35.664 0.024 35.688 ;
    END
  END wd_in[115]
  PIN addr_in[0]
    DIRECTION INPUT ;
    USE SIGNAL ;
    SHAPE ABUTMENT ;
    PORT
      LAYER M4 ;
      RECT 0.000 38.160 0.024 38.184 ;
    END
  END addr_in[0]
  PIN addr_in[1]
    DIRECTION INPUT ;
    USE SIGNAL ;
    SHAPE ABUTMENT ;
    PORT
      LAYER M4 ;
      RECT 0.000 38.304 0.024 38.328 ;
    END
  END addr_in[1]
  PIN addr_in[2]
    DIRECTION INPUT ;
    USE SIGNAL ;
    SHAPE ABUTMENT ;
    PORT
      LAYER M4 ;
      RECT 0.000 38.448 0.024 38.472 ;
    END
  END addr_in[2]
  PIN addr_in[3]
    DIRECTION INPUT ;
    USE SIGNAL ;
    SHAPE ABUTMENT ;
    PORT
      LAYER M4 ;
      RECT 0.000 38.592 0.024 38.616 ;
    END
  END addr_in[3]
  PIN addr_in[4]
    DIRECTION INPUT ;
    USE SIGNAL ;
    SHAPE ABUTMENT ;
    PORT
      LAYER M4 ;
      RECT 0.000 38.736 0.024 38.760 ;
    END
  END addr_in[4]
  PIN addr_in[5]
    DIRECTION INPUT ;
    USE SIGNAL ;
    SHAPE ABUTMENT ;
    PORT
      LAYER M4 ;
      RECT 0.000 38.880 0.024 38.904 ;
    END
  END addr_in[5]
  PIN addr_in[6]
    DIRECTION INPUT ;
    USE SIGNAL ;
    SHAPE ABUTMENT ;
    PORT
      LAYER M4 ;
      RECT 0.000 39.024 0.024 39.048 ;
    END
  END addr_in[6]
  PIN we_in
    DIRECTION INPUT ;
    USE SIGNAL ;
    SHAPE ABUTMENT ;
    PORT
      LAYER M4 ;
      RECT 0.000 41.520 0.024 41.544 ;
    END
  END we_in
  PIN ce_in
    DIRECTION INPUT ;
    USE SIGNAL ;
    SHAPE ABUTMENT ;
    PORT
      LAYER M4 ;
      RECT 0.000 41.664 0.024 41.688 ;
    END
  END ce_in
  PIN clk
    DIRECTION INPUT ;
    USE SIGNAL ;
    SHAPE ABUTMENT ;
    PORT
      LAYER M4 ;
      RECT 0.000 41.808 0.024 41.832 ;
    END
  END clk
  PIN VSS
    DIRECTION INOUT ;
    USE GROUND ;
    PORT
      LAYER M4 ;
      RECT 0.048 0.000 15.152 0.096 ;
      RECT 0.048 0.768 15.152 0.864 ;
      RECT 0.048 1.536 15.152 1.632 ;
      RECT 0.048 2.304 15.152 2.400 ;
      RECT 0.048 3.072 15.152 3.168 ;
      RECT 0.048 3.840 15.152 3.936 ;
      RECT 0.048 4.608 15.152 4.704 ;
      RECT 0.048 5.376 15.152 5.472 ;
      RECT 0.048 6.144 15.152 6.240 ;
      RECT 0.048 6.912 15.152 7.008 ;
      RECT 0.048 7.680 15.152 7.776 ;
      RECT 0.048 8.448 15.152 8.544 ;
      RECT 0.048 9.216 15.152 9.312 ;
      RECT 0.048 9.984 15.152 10.080 ;
      RECT 0.048 10.752 15.152 10.848 ;
      RECT 0.048 11.520 15.152 11.616 ;
      RECT 0.048 12.288 15.152 12.384 ;
      RECT 0.048 13.056 15.152 13.152 ;
      RECT 0.048 13.824 15.152 13.920 ;
      RECT 0.048 14.592 15.152 14.688 ;
      RECT 0.048 15.360 15.152 15.456 ;
      RECT 0.048 16.128 15.152 16.224 ;
      RECT 0.048 16.896 15.152 16.992 ;
      RECT 0.048 17.664 15.152 17.760 ;
      RECT 0.048 18.432 15.152 18.528 ;
      RECT 0.048 19.200 15.152 19.296 ;
      RECT 0.048 19.968 15.152 20.064 ;
      RECT 0.048 20.736 15.152 20.832 ;
      RECT 0.048 21.504 15.152 21.600 ;
      RECT 0.048 22.272 15.152 22.368 ;
      RECT 0.048 23.040 15.152 23.136 ;
      RECT 0.048 23.808 15.152 23.904 ;
      RECT 0.048 24.576 15.152 24.672 ;
      RECT 0.048 25.344 15.152 25.440 ;
      RECT 0.048 26.112 15.152 26.208 ;
      RECT 0.048 26.880 15.152 26.976 ;
      RECT 0.048 27.648 15.152 27.744 ;
      RECT 0.048 28.416 15.152 28.512 ;
      RECT 0.048 29.184 15.152 29.280 ;
      RECT 0.048 29.952 15.152 30.048 ;
      RECT 0.048 30.720 15.152 30.816 ;
      RECT 0.048 31.488 15.152 31.584 ;
      RECT 0.048 32.256 15.152 32.352 ;
      RECT 0.048 33.024 15.152 33.120 ;
      RECT 0.048 33.792 15.152 33.888 ;
      RECT 0.048 34.560 15.152 34.656 ;
      RECT 0.048 35.328 15.152 35.424 ;
      RECT 0.048 36.096 15.152 36.192 ;
      RECT 0.048 36.864 15.152 36.960 ;
      RECT 0.048 37.632 15.152 37.728 ;
      RECT 0.048 38.400 15.152 38.496 ;
      RECT 0.048 39.168 15.152 39.264 ;
      RECT 0.048 39.936 15.152 40.032 ;
      RECT 0.048 40.704 15.152 40.800 ;
      RECT 0.048 41.472 15.152 41.568 ;
    END
  END VSS
  PIN VDD
    DIRECTION INOUT ;
    USE POWER ;
    PORT
      LAYER M4 ;
      RECT 0.048 0.384 15.152 0.480 ;
      RECT 0.048 1.152 15.152 1.248 ;
      RECT 0.048 1.920 15.152 2.016 ;
      RECT 0.048 2.688 15.152 2.784 ;
      RECT 0.048 3.456 15.152 3.552 ;
      RECT 0.048 4.224 15.152 4.320 ;
      RECT 0.048 4.992 15.152 5.088 ;
      RECT 0.048 5.760 15.152 5.856 ;
      RECT 0.048 6.528 15.152 6.624 ;
      RECT 0.048 7.296 15.152 7.392 ;
      RECT 0.048 8.064 15.152 8.160 ;
      RECT 0.048 8.832 15.152 8.928 ;
      RECT 0.048 9.600 15.152 9.696 ;
      RECT 0.048 10.368 15.152 10.464 ;
      RECT 0.048 11.136 15.152 11.232 ;
      RECT 0.048 11.904 15.152 12.000 ;
      RECT 0.048 12.672 15.152 12.768 ;
      RECT 0.048 13.440 15.152 13.536 ;
      RECT 0.048 14.208 15.152 14.304 ;
      RECT 0.048 14.976 15.152 15.072 ;
      RECT 0.048 15.744 15.152 15.840 ;
      RECT 0.048 16.512 15.152 16.608 ;
      RECT 0.048 17.280 15.152 17.376 ;
      RECT 0.048 18.048 15.152 18.144 ;
      RECT 0.048 18.816 15.152 18.912 ;
      RECT 0.048 19.584 15.152 19.680 ;
      RECT 0.048 20.352 15.152 20.448 ;
      RECT 0.048 21.120 15.152 21.216 ;
      RECT 0.048 21.888 15.152 21.984 ;
      RECT 0.048 22.656 15.152 22.752 ;
      RECT 0.048 23.424 15.152 23.520 ;
      RECT 0.048 24.192 15.152 24.288 ;
      RECT 0.048 24.960 15.152 25.056 ;
      RECT 0.048 25.728 15.152 25.824 ;
      RECT 0.048 26.496 15.152 26.592 ;
      RECT 0.048 27.264 15.152 27.360 ;
      RECT 0.048 28.032 15.152 28.128 ;
      RECT 0.048 28.800 15.152 28.896 ;
      RECT 0.048 29.568 15.152 29.664 ;
      RECT 0.048 30.336 15.152 30.432 ;
      RECT 0.048 31.104 15.152 31.200 ;
      RECT 0.048 31.872 15.152 31.968 ;
      RECT 0.048 32.640 15.152 32.736 ;
      RECT 0.048 33.408 15.152 33.504 ;
      RECT 0.048 34.176 15.152 34.272 ;
      RECT 0.048 34.944 15.152 35.040 ;
      RECT 0.048 35.712 15.152 35.808 ;
      RECT 0.048 36.480 15.152 36.576 ;
      RECT 0.048 37.248 15.152 37.344 ;
      RECT 0.048 38.016 15.152 38.112 ;
      RECT 0.048 38.784 15.152 38.880 ;
      RECT 0.048 39.552 15.152 39.648 ;
      RECT 0.048 40.320 15.152 40.416 ;
      RECT 0.048 41.088 15.152 41.184 ;
      RECT 0.048 41.856 15.152 41.952 ;
    END
  END VDD
  OBS
    LAYER M1 ;
    RECT 0 0 15.200 42.000 ;
    LAYER M2 ;
    RECT 0 0 15.200 42.000 ;
    LAYER M3 ;
    RECT 0 0 15.200 42.000 ;
    LAYER M4 ;
    RECT 0 0 15.200 42.000 ;
  END
END sram_asap7_116x128_1rw

END LIBRARY
